VERSION 5.7 ;
  NOWIREEXTENSIONATPIN ON ;
  DIVIDERCHAR "/" ;
  BUSBITCHARS "[]" ;
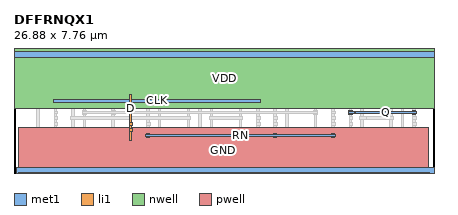
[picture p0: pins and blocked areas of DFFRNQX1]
MACRO DFFRNQX1
  CLASS CORE ;
  FOREIGN DFFRNQX1 ;
  ORIGIN 0.000 0.000 ;
  SIZE 26.880 BY 7.760 ;
  SYMMETRY X Y ;
  SITE unitrh ;
  PIN Q
    DIRECTION OUTPUT ;
    USE SIGNAL ;
    ANTENNADIFFAREA 1.351900 ;
    PORT
      LAYER met1 ;
        RECT 25.480 3.965 25.710 3.995 ;
        RECT 21.845 3.795 25.740 3.965 ;
        RECT 25.480 3.765 25.710 3.795 ;
    END
    PORT
      LAYER met1 ;
        RECT 21.410 3.965 21.640 3.995 ;
        RECT 21.380 3.795 21.790 3.965 ;
        RECT 21.410 3.765 21.640 3.795 ;
    END
  END Q
  PIN D
    DIRECTION INPUT ;
    USE SIGNAL ;
    ANTENNAGATEAREA 1.014850 ;
    PORT
      LAYER li1 ;
        RECT 7.380 3.225 7.550 5.045 ;
        RECT 7.380 3.055 7.605 3.225 ;
        RECT 7.380 2.855 7.550 3.055 ;
        RECT 7.380 2.685 7.605 2.855 ;
        RECT 7.380 2.095 7.550 2.685 ;
    END
  END D
  PIN CLK
    DIRECTION INPUT ;
    USE SIGNAL ;
    ANTENNAGATEAREA 2.029700 ;
    PORT
      LAYER met1 ;
        RECT 2.540 4.705 2.770 4.735 ;
        RECT 15.490 4.705 15.720 4.735 ;
        RECT 2.510 4.535 15.750 4.705 ;
        RECT 2.540 4.505 2.770 4.535 ;
        RECT 15.490 4.505 15.720 4.535 ;
    END
  END CLK
  PIN RN
    DIRECTION INPUT ;
    USE SIGNAL ;
    ANTENNAGATEAREA 3.069350 ;
    PORT
      LAYER met1 ;
        RECT 8.460 2.485 8.690 2.515 ;
        RECT 16.600 2.485 16.830 2.515 ;
        RECT 20.300 2.485 20.530 2.515 ;
        RECT 8.430 2.315 20.560 2.485 ;
        RECT 8.460 2.285 8.690 2.315 ;
        RECT 16.600 2.285 16.830 2.315 ;
        RECT 20.300 2.285 20.530 2.315 ;
    END
  END RN
  PIN VDD
    DIRECTION INOUT ;
    USE POWER ;
    SHAPE ABUTMENT ;
    PORT
      LAYER nwell ;
        RECT 0.000 4.110 26.880 7.940 ;
      LAYER met1 ;
        RECT 0.000 7.410 26.880 7.760 ;
    END
  END VDD
  PIN GND
    DIRECTION INOUT ;
    USE GROUND ;
    SHAPE ABUTMENT ;
    PORT
      LAYER pwell ;
        RECT 0.265 0.035 26.505 2.900 ;
        RECT 0.265 0.010 26.560 0.035 ;
        RECT 0.320 0.000 26.560 0.010 ;
      LAYER met1 ;
        RECT 0.180 0.000 26.880 0.350 ;
    END
  END GND
  OBS
      LAYER li1 ;
        RECT 0.000 7.410 26.880 7.760 ;
        RECT 0.265 4.290 0.605 7.410 ;
        RECT 1.440 5.395 1.610 7.410 ;
        RECT 1.880 5.420 2.050 7.200 ;
        RECT 2.320 5.735 2.490 7.410 ;
        RECT 2.760 5.420 2.930 7.200 ;
        RECT 3.200 5.735 3.370 7.410 ;
        RECT 3.640 5.420 3.810 7.200 ;
        RECT 4.080 5.735 4.250 7.410 ;
        RECT 1.880 5.250 4.590 5.420 ;
        RECT 0.265 0.350 0.605 2.900 ;
        RECT 1.460 2.095 1.630 5.045 ;
        RECT 2.570 4.705 2.740 5.045 ;
        RECT 2.570 4.535 2.795 4.705 ;
        RECT 2.570 3.965 2.740 4.535 ;
        RECT 2.570 3.795 2.795 3.965 ;
        RECT 2.570 3.595 2.740 3.795 ;
        RECT 2.570 3.425 2.795 3.595 ;
        RECT 2.570 3.225 2.740 3.425 ;
        RECT 2.570 3.055 2.795 3.225 ;
        RECT 2.570 2.855 2.740 3.055 ;
        RECT 2.570 2.685 2.795 2.855 ;
        RECT 2.570 2.095 2.740 2.685 ;
        RECT 3.680 2.095 3.850 5.045 ;
        RECT 0.940 1.855 1.110 1.935 ;
        RECT 1.910 1.855 2.080 1.935 ;
        RECT 2.880 1.855 3.050 1.935 ;
        RECT 0.940 1.685 3.050 1.855 ;
        RECT 0.940 0.555 1.110 1.685 ;
        RECT 1.425 0.350 1.595 1.310 ;
        RECT 1.910 0.805 2.080 1.685 ;
        RECT 2.880 1.605 3.050 1.685 ;
        RECT 2.400 1.260 2.570 1.340 ;
        RECT 3.450 1.260 3.620 1.935 ;
        RECT 4.420 1.930 4.590 5.250 ;
        RECT 5.075 4.290 5.415 7.410 ;
        RECT 6.250 5.395 6.420 7.410 ;
        RECT 6.690 5.420 6.860 7.200 ;
        RECT 7.130 5.735 7.300 7.410 ;
        RECT 7.570 5.420 7.740 7.200 ;
        RECT 8.010 5.735 8.180 7.410 ;
        RECT 8.450 5.420 8.620 7.200 ;
        RECT 8.890 5.735 9.060 7.410 ;
        RECT 6.690 5.250 9.400 5.420 ;
        RECT 2.400 1.090 3.620 1.260 ;
        RECT 2.400 1.010 2.570 1.090 ;
        RECT 2.880 0.805 3.050 0.885 ;
        RECT 1.910 0.635 3.050 0.805 ;
        RECT 1.910 0.555 2.080 0.635 ;
        RECT 2.880 0.555 3.050 0.635 ;
        RECT 3.450 0.805 3.620 1.090 ;
        RECT 3.935 1.760 4.590 1.930 ;
        RECT 3.935 1.025 4.105 1.760 ;
        RECT 4.420 0.805 4.590 1.575 ;
        RECT 3.450 0.635 4.590 0.805 ;
        RECT 3.450 0.555 3.620 0.635 ;
        RECT 4.420 0.555 4.590 0.635 ;
        RECT 5.075 0.350 5.415 2.900 ;
        RECT 6.270 2.095 6.440 5.045 ;
        RECT 8.490 3.225 8.660 5.045 ;
        RECT 8.490 3.055 8.715 3.225 ;
        RECT 8.490 2.855 8.660 3.055 ;
        RECT 8.490 2.685 8.715 2.855 ;
        RECT 8.490 2.485 8.660 2.685 ;
        RECT 8.490 2.315 8.715 2.485 ;
        RECT 8.490 2.095 8.660 2.315 ;
        RECT 5.750 1.855 5.920 1.935 ;
        RECT 6.720 1.855 6.890 1.935 ;
        RECT 7.690 1.855 7.860 1.935 ;
        RECT 5.750 1.685 7.860 1.855 ;
        RECT 5.750 0.555 5.920 1.685 ;
        RECT 6.235 0.350 6.405 1.310 ;
        RECT 6.720 0.805 6.890 1.685 ;
        RECT 7.690 1.605 7.860 1.685 ;
        RECT 7.210 1.260 7.380 1.340 ;
        RECT 8.260 1.260 8.430 1.935 ;
        RECT 9.230 1.930 9.400 5.250 ;
        RECT 9.885 4.290 10.225 7.410 ;
        RECT 10.760 5.315 10.930 7.410 ;
        RECT 11.200 5.465 11.370 7.200 ;
        RECT 11.640 5.735 11.810 7.410 ;
        RECT 12.080 5.465 12.250 7.200 ;
        RECT 12.520 5.735 12.690 7.410 ;
        RECT 11.200 5.295 12.730 5.465 ;
        RECT 7.210 1.090 8.430 1.260 ;
        RECT 7.210 1.010 7.380 1.090 ;
        RECT 7.690 0.805 7.860 0.885 ;
        RECT 6.720 0.635 7.860 0.805 ;
        RECT 6.720 0.555 6.890 0.635 ;
        RECT 7.690 0.555 7.860 0.635 ;
        RECT 8.260 0.805 8.430 1.090 ;
        RECT 8.745 1.760 9.400 1.930 ;
        RECT 8.745 1.025 8.915 1.760 ;
        RECT 9.230 0.805 9.400 1.575 ;
        RECT 8.260 0.635 9.400 0.805 ;
        RECT 8.260 0.555 8.430 0.635 ;
        RECT 9.230 0.555 9.400 0.635 ;
        RECT 9.885 0.350 10.225 2.900 ;
        RECT 11.080 2.095 11.250 5.045 ;
        RECT 11.850 4.890 12.020 5.045 ;
        RECT 11.820 4.715 12.020 4.890 ;
        RECT 11.820 2.095 11.990 4.715 ;
        RECT 10.665 1.845 10.835 1.925 ;
        RECT 11.635 1.845 11.805 1.925 ;
        RECT 12.560 1.920 12.730 5.295 ;
        RECT 13.215 4.290 13.555 7.410 ;
        RECT 14.390 5.395 14.560 7.410 ;
        RECT 14.830 5.420 15.000 7.200 ;
        RECT 15.270 5.735 15.440 7.410 ;
        RECT 15.710 5.420 15.880 7.200 ;
        RECT 16.150 5.735 16.320 7.410 ;
        RECT 16.590 5.420 16.760 7.200 ;
        RECT 17.030 5.735 17.200 7.410 ;
        RECT 14.830 5.250 17.540 5.420 ;
        RECT 10.665 1.675 11.805 1.845 ;
        RECT 10.665 0.545 10.835 1.675 ;
        RECT 11.150 0.350 11.320 1.300 ;
        RECT 11.635 0.795 11.805 1.675 ;
        RECT 12.120 1.750 12.730 1.920 ;
        RECT 12.120 1.015 12.290 1.750 ;
        RECT 12.605 0.795 12.775 1.565 ;
        RECT 11.635 0.625 12.775 0.795 ;
        RECT 11.635 0.545 11.805 0.625 ;
        RECT 12.605 0.545 12.775 0.625 ;
        RECT 13.215 0.350 13.555 2.900 ;
        RECT 14.410 2.095 14.580 5.045 ;
        RECT 15.520 4.705 15.690 5.045 ;
        RECT 15.520 4.535 15.745 4.705 ;
        RECT 15.520 3.595 15.690 4.535 ;
        RECT 16.630 3.595 16.800 5.045 ;
        RECT 15.520 3.425 15.745 3.595 ;
        RECT 16.630 3.425 16.855 3.595 ;
        RECT 15.520 3.225 15.690 3.425 ;
        RECT 16.630 3.225 16.800 3.425 ;
        RECT 15.520 3.055 15.745 3.225 ;
        RECT 16.630 3.055 16.855 3.225 ;
        RECT 15.520 2.855 15.690 3.055 ;
        RECT 16.630 2.855 16.800 3.055 ;
        RECT 15.520 2.685 15.745 2.855 ;
        RECT 16.630 2.685 16.855 2.855 ;
        RECT 15.520 2.095 15.690 2.685 ;
        RECT 16.630 2.485 16.800 2.685 ;
        RECT 16.630 2.315 16.855 2.485 ;
        RECT 16.630 2.095 16.800 2.315 ;
        RECT 13.890 1.855 14.060 1.935 ;
        RECT 14.860 1.855 15.030 1.935 ;
        RECT 15.830 1.855 16.000 1.935 ;
        RECT 13.890 1.685 16.000 1.855 ;
        RECT 13.890 0.555 14.060 1.685 ;
        RECT 14.375 0.350 14.545 1.310 ;
        RECT 14.860 0.805 15.030 1.685 ;
        RECT 15.830 1.605 16.000 1.685 ;
        RECT 15.350 1.260 15.520 1.340 ;
        RECT 16.400 1.260 16.570 1.935 ;
        RECT 17.370 1.930 17.540 5.250 ;
        RECT 18.025 4.290 18.365 7.410 ;
        RECT 19.200 5.395 19.370 7.410 ;
        RECT 19.640 5.420 19.810 7.200 ;
        RECT 20.080 5.735 20.250 7.410 ;
        RECT 20.520 5.420 20.690 7.200 ;
        RECT 20.960 5.735 21.130 7.410 ;
        RECT 21.400 5.420 21.570 7.200 ;
        RECT 21.840 5.735 22.010 7.410 ;
        RECT 19.640 5.250 22.350 5.420 ;
        RECT 15.350 1.090 16.570 1.260 ;
        RECT 15.350 1.010 15.520 1.090 ;
        RECT 15.830 0.805 16.000 0.885 ;
        RECT 14.860 0.635 16.000 0.805 ;
        RECT 14.860 0.555 15.030 0.635 ;
        RECT 15.830 0.555 16.000 0.635 ;
        RECT 16.400 0.805 16.570 1.090 ;
        RECT 16.885 1.760 17.540 1.930 ;
        RECT 16.885 1.025 17.055 1.760 ;
        RECT 17.370 0.805 17.540 1.575 ;
        RECT 16.400 0.635 17.540 0.805 ;
        RECT 16.400 0.555 16.570 0.635 ;
        RECT 17.370 0.555 17.540 0.635 ;
        RECT 18.025 0.350 18.365 2.900 ;
        RECT 19.220 2.095 19.390 5.045 ;
        RECT 20.330 4.705 20.500 5.045 ;
        RECT 21.440 4.705 21.610 5.045 ;
        RECT 20.330 4.535 20.555 4.705 ;
        RECT 21.440 4.535 21.665 4.705 ;
        RECT 20.330 3.965 20.500 4.535 ;
        RECT 21.440 3.965 21.610 4.535 ;
        RECT 20.330 3.795 20.555 3.965 ;
        RECT 21.440 3.795 21.665 3.965 ;
        RECT 20.330 3.595 20.500 3.795 ;
        RECT 21.440 3.595 21.610 3.795 ;
        RECT 20.330 3.425 20.555 3.595 ;
        RECT 21.440 3.425 21.665 3.595 ;
        RECT 20.330 3.225 20.500 3.425 ;
        RECT 21.440 3.225 21.610 3.425 ;
        RECT 20.330 3.055 20.555 3.225 ;
        RECT 21.440 3.055 21.665 3.225 ;
        RECT 20.330 2.855 20.500 3.055 ;
        RECT 21.440 2.855 21.610 3.055 ;
        RECT 20.330 2.685 20.555 2.855 ;
        RECT 21.440 2.685 21.665 2.855 ;
        RECT 20.330 2.485 20.500 2.685 ;
        RECT 20.330 2.315 20.555 2.485 ;
        RECT 20.330 2.095 20.500 2.315 ;
        RECT 21.440 2.095 21.610 2.685 ;
        RECT 18.700 1.855 18.870 1.935 ;
        RECT 19.670 1.855 19.840 1.935 ;
        RECT 20.640 1.855 20.810 1.935 ;
        RECT 18.700 1.685 20.810 1.855 ;
        RECT 18.700 0.555 18.870 1.685 ;
        RECT 19.185 0.350 19.355 1.310 ;
        RECT 19.670 0.805 19.840 1.685 ;
        RECT 20.640 1.605 20.810 1.685 ;
        RECT 20.160 1.260 20.330 1.340 ;
        RECT 21.210 1.260 21.380 1.935 ;
        RECT 22.180 1.930 22.350 5.250 ;
        RECT 22.835 4.290 23.175 7.410 ;
        RECT 23.710 5.315 23.880 7.410 ;
        RECT 24.150 5.465 24.320 7.200 ;
        RECT 24.590 5.735 24.760 7.410 ;
        RECT 25.030 5.465 25.200 7.200 ;
        RECT 25.470 5.735 25.640 7.410 ;
        RECT 24.150 5.295 25.680 5.465 ;
        RECT 25.510 5.075 25.680 5.295 ;
        RECT 20.160 1.090 21.380 1.260 ;
        RECT 20.160 1.010 20.330 1.090 ;
        RECT 20.640 0.805 20.810 0.885 ;
        RECT 19.670 0.635 20.810 0.805 ;
        RECT 19.670 0.555 19.840 0.635 ;
        RECT 20.640 0.555 20.810 0.635 ;
        RECT 21.210 0.805 21.380 1.090 ;
        RECT 21.695 1.760 22.350 1.930 ;
        RECT 21.695 1.025 21.865 1.760 ;
        RECT 22.180 0.805 22.350 1.575 ;
        RECT 21.210 0.635 22.350 0.805 ;
        RECT 21.210 0.555 21.380 0.635 ;
        RECT 22.180 0.555 22.350 0.635 ;
        RECT 22.835 0.350 23.175 2.900 ;
        RECT 24.030 2.095 24.200 5.045 ;
        RECT 24.800 4.890 24.970 5.045 ;
        RECT 24.770 4.715 24.970 4.890 ;
        RECT 25.510 4.905 25.735 5.075 ;
        RECT 24.770 2.095 24.940 4.715 ;
        RECT 25.510 4.705 25.680 4.905 ;
        RECT 25.510 4.535 25.735 4.705 ;
        RECT 25.510 4.335 25.680 4.535 ;
        RECT 25.510 4.165 25.735 4.335 ;
        RECT 26.165 4.290 26.505 7.410 ;
        RECT 25.510 3.965 25.680 4.165 ;
        RECT 25.510 3.795 25.735 3.965 ;
        RECT 25.510 3.595 25.680 3.795 ;
        RECT 25.510 3.425 25.735 3.595 ;
        RECT 25.510 3.225 25.680 3.425 ;
        RECT 25.510 3.055 25.735 3.225 ;
        RECT 25.510 2.855 25.680 3.055 ;
        RECT 25.510 2.685 25.735 2.855 ;
        RECT 25.510 2.485 25.680 2.685 ;
        RECT 25.510 2.315 25.735 2.485 ;
        RECT 23.615 1.845 23.785 1.925 ;
        RECT 24.585 1.845 24.755 1.925 ;
        RECT 25.510 1.920 25.680 2.315 ;
        RECT 23.615 1.675 24.755 1.845 ;
        RECT 23.615 0.545 23.785 1.675 ;
        RECT 24.100 0.350 24.270 1.300 ;
        RECT 24.585 0.795 24.755 1.675 ;
        RECT 25.070 1.750 25.680 1.920 ;
        RECT 25.070 1.015 25.240 1.750 ;
        RECT 25.555 0.795 25.725 1.565 ;
        RECT 24.585 0.625 25.725 0.795 ;
        RECT 24.585 0.545 24.755 0.625 ;
        RECT 25.555 0.545 25.725 0.625 ;
        RECT 26.165 0.350 26.505 2.900 ;
        RECT 0.180 0.000 26.880 0.350 ;
      LAYER mcon ;
        RECT 0.720 7.495 0.890 7.665 ;
        RECT 1.090 7.495 1.260 7.665 ;
        RECT 1.460 7.495 1.630 7.665 ;
        RECT 1.830 7.495 2.000 7.665 ;
        RECT 2.200 7.495 2.370 7.665 ;
        RECT 2.570 7.495 2.740 7.665 ;
        RECT 2.940 7.495 3.110 7.665 ;
        RECT 3.310 7.495 3.480 7.665 ;
        RECT 3.680 7.495 3.850 7.665 ;
        RECT 4.050 7.495 4.220 7.665 ;
        RECT 4.420 7.495 4.590 7.665 ;
        RECT 4.790 7.495 4.960 7.665 ;
        RECT 5.530 7.495 5.700 7.665 ;
        RECT 5.900 7.495 6.070 7.665 ;
        RECT 6.270 7.495 6.440 7.665 ;
        RECT 6.640 7.495 6.810 7.665 ;
        RECT 7.010 7.495 7.180 7.665 ;
        RECT 7.380 7.495 7.550 7.665 ;
        RECT 7.750 7.495 7.920 7.665 ;
        RECT 8.120 7.495 8.290 7.665 ;
        RECT 8.490 7.495 8.660 7.665 ;
        RECT 8.860 7.495 9.030 7.665 ;
        RECT 9.230 7.495 9.400 7.665 ;
        RECT 9.600 7.495 9.770 7.665 ;
        RECT 10.340 7.495 10.510 7.665 ;
        RECT 10.710 7.495 10.880 7.665 ;
        RECT 11.080 7.495 11.250 7.665 ;
        RECT 11.450 7.495 11.620 7.665 ;
        RECT 11.820 7.495 11.990 7.665 ;
        RECT 12.190 7.495 12.360 7.665 ;
        RECT 12.560 7.495 12.730 7.665 ;
        RECT 12.930 7.495 13.100 7.665 ;
        RECT 13.670 7.495 13.840 7.665 ;
        RECT 14.040 7.495 14.210 7.665 ;
        RECT 14.410 7.495 14.580 7.665 ;
        RECT 14.780 7.495 14.950 7.665 ;
        RECT 15.150 7.495 15.320 7.665 ;
        RECT 15.520 7.495 15.690 7.665 ;
        RECT 15.890 7.495 16.060 7.665 ;
        RECT 16.260 7.495 16.430 7.665 ;
        RECT 16.630 7.495 16.800 7.665 ;
        RECT 17.000 7.495 17.170 7.665 ;
        RECT 17.370 7.495 17.540 7.665 ;
        RECT 17.740 7.495 17.910 7.665 ;
        RECT 18.480 7.495 18.650 7.665 ;
        RECT 18.850 7.495 19.020 7.665 ;
        RECT 19.220 7.495 19.390 7.665 ;
        RECT 19.590 7.495 19.760 7.665 ;
        RECT 19.960 7.495 20.130 7.665 ;
        RECT 20.330 7.495 20.500 7.665 ;
        RECT 20.700 7.495 20.870 7.665 ;
        RECT 21.070 7.495 21.240 7.665 ;
        RECT 21.440 7.495 21.610 7.665 ;
        RECT 21.810 7.495 21.980 7.665 ;
        RECT 22.180 7.495 22.350 7.665 ;
        RECT 22.550 7.495 22.720 7.665 ;
        RECT 23.290 7.495 23.460 7.665 ;
        RECT 23.660 7.495 23.830 7.665 ;
        RECT 24.030 7.495 24.200 7.665 ;
        RECT 24.400 7.495 24.570 7.665 ;
        RECT 24.770 7.495 24.940 7.665 ;
        RECT 25.140 7.495 25.310 7.665 ;
        RECT 25.510 7.495 25.680 7.665 ;
        RECT 25.880 7.495 26.050 7.665 ;
        RECT 1.460 4.165 1.630 4.335 ;
        RECT 3.680 3.425 3.850 3.595 ;
        RECT 4.420 3.795 4.590 3.965 ;
        RECT 6.270 3.795 6.440 3.965 ;
        RECT 9.230 3.425 9.400 3.595 ;
        RECT 11.080 3.425 11.250 3.595 ;
        RECT 11.820 4.165 11.990 4.335 ;
        RECT 12.560 3.425 12.730 3.595 ;
        RECT 14.410 3.425 14.580 3.595 ;
        RECT 17.370 4.165 17.540 4.335 ;
        RECT 19.220 3.795 19.390 3.965 ;
        RECT 22.180 3.425 22.350 3.595 ;
        RECT 24.030 3.425 24.200 3.595 ;
        RECT 24.770 4.165 24.940 4.335 ;
        RECT 0.720 0.095 0.890 0.265 ;
        RECT 1.090 0.095 1.260 0.265 ;
        RECT 1.460 0.095 1.630 0.265 ;
        RECT 1.830 0.095 2.000 0.265 ;
        RECT 2.200 0.095 2.370 0.265 ;
        RECT 2.570 0.095 2.740 0.265 ;
        RECT 2.940 0.095 3.110 0.265 ;
        RECT 3.310 0.095 3.480 0.265 ;
        RECT 3.680 0.095 3.850 0.265 ;
        RECT 4.050 0.095 4.220 0.265 ;
        RECT 4.420 0.095 4.590 0.265 ;
        RECT 4.790 0.095 4.960 0.265 ;
        RECT 5.530 0.095 5.700 0.265 ;
        RECT 5.900 0.095 6.070 0.265 ;
        RECT 6.270 0.095 6.440 0.265 ;
        RECT 6.640 0.095 6.810 0.265 ;
        RECT 7.010 0.095 7.180 0.265 ;
        RECT 7.380 0.095 7.550 0.265 ;
        RECT 7.750 0.095 7.920 0.265 ;
        RECT 8.120 0.095 8.290 0.265 ;
        RECT 8.490 0.095 8.660 0.265 ;
        RECT 8.860 0.095 9.030 0.265 ;
        RECT 9.230 0.095 9.400 0.265 ;
        RECT 9.600 0.095 9.770 0.265 ;
        RECT 10.340 0.095 10.510 0.265 ;
        RECT 10.710 0.095 10.880 0.265 ;
        RECT 11.080 0.095 11.250 0.265 ;
        RECT 11.450 0.095 11.620 0.265 ;
        RECT 11.820 0.095 11.990 0.265 ;
        RECT 12.190 0.095 12.360 0.265 ;
        RECT 12.560 0.095 12.730 0.265 ;
        RECT 12.930 0.095 13.100 0.265 ;
        RECT 13.670 0.095 13.840 0.265 ;
        RECT 14.040 0.095 14.210 0.265 ;
        RECT 14.410 0.095 14.580 0.265 ;
        RECT 14.780 0.095 14.950 0.265 ;
        RECT 15.150 0.095 15.320 0.265 ;
        RECT 15.520 0.095 15.690 0.265 ;
        RECT 15.890 0.095 16.060 0.265 ;
        RECT 16.260 0.095 16.430 0.265 ;
        RECT 16.630 0.095 16.800 0.265 ;
        RECT 17.000 0.095 17.170 0.265 ;
        RECT 17.370 0.095 17.540 0.265 ;
        RECT 17.740 0.095 17.910 0.265 ;
        RECT 18.480 0.095 18.650 0.265 ;
        RECT 18.850 0.095 19.020 0.265 ;
        RECT 19.220 0.095 19.390 0.265 ;
        RECT 19.590 0.095 19.760 0.265 ;
        RECT 19.960 0.095 20.130 0.265 ;
        RECT 20.330 0.095 20.500 0.265 ;
        RECT 20.700 0.095 20.870 0.265 ;
        RECT 21.070 0.095 21.240 0.265 ;
        RECT 21.440 0.095 21.610 0.265 ;
        RECT 21.810 0.095 21.980 0.265 ;
        RECT 22.180 0.095 22.350 0.265 ;
        RECT 22.550 0.095 22.720 0.265 ;
        RECT 23.290 0.095 23.460 0.265 ;
        RECT 23.660 0.095 23.830 0.265 ;
        RECT 24.030 0.095 24.200 0.265 ;
        RECT 24.400 0.095 24.570 0.265 ;
        RECT 24.770 0.095 24.940 0.265 ;
        RECT 25.140 0.095 25.310 0.265 ;
        RECT 25.510 0.095 25.680 0.265 ;
        RECT 25.880 0.095 26.050 0.265 ;
      LAYER met1 ;
        RECT 1.430 4.335 1.660 4.365 ;
        RECT 11.790 4.335 12.020 4.365 ;
        RECT 17.340 4.335 17.570 4.365 ;
        RECT 24.740 4.335 24.970 4.365 ;
        RECT 1.400 4.165 25.000 4.335 ;
        RECT 1.430 4.135 1.660 4.165 ;
        RECT 11.790 4.135 12.020 4.165 ;
        RECT 17.340 4.135 17.570 4.165 ;
        RECT 24.740 4.135 24.970 4.165 ;
        RECT 4.390 3.965 4.620 3.995 ;
        RECT 6.240 3.965 6.470 3.995 ;
        RECT 19.190 3.965 19.420 3.995 ;
        RECT 4.360 3.795 19.450 3.965 ;
        RECT 4.390 3.765 4.620 3.795 ;
        RECT 6.240 3.765 6.470 3.795 ;
        RECT 19.190 3.765 19.420 3.795 ;
        RECT 3.650 3.595 3.880 3.625 ;
        RECT 9.200 3.595 9.430 3.625 ;
        RECT 11.050 3.595 11.280 3.625 ;
        RECT 12.530 3.595 12.760 3.625 ;
        RECT 14.380 3.595 14.610 3.625 ;
        RECT 22.150 3.595 22.380 3.625 ;
        RECT 24.000 3.595 24.230 3.625 ;
        RECT 3.620 3.425 11.310 3.595 ;
        RECT 12.500 3.425 14.640 3.595 ;
        RECT 22.120 3.425 22.530 3.595 ;
        RECT 22.585 3.425 24.260 3.595 ;
        RECT 3.650 3.395 3.880 3.425 ;
        RECT 9.200 3.395 9.430 3.425 ;
        RECT 11.050 3.395 11.280 3.425 ;
        RECT 12.530 3.395 12.760 3.425 ;
        RECT 14.380 3.395 14.610 3.425 ;
        RECT 22.150 3.395 22.380 3.425 ;
        RECT 24.000 3.395 24.230 3.425 ;
  END
END DFFRNQX1
END LIBRARY

